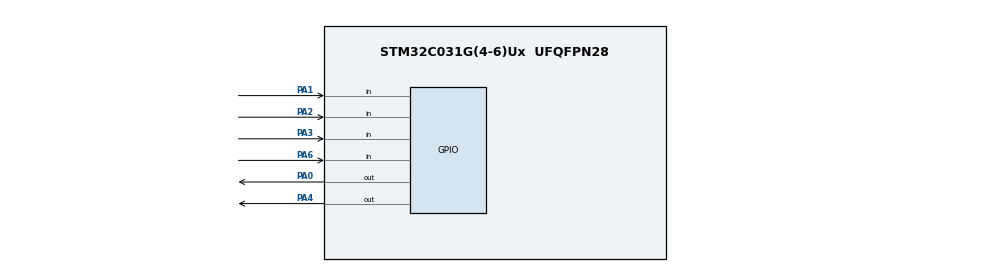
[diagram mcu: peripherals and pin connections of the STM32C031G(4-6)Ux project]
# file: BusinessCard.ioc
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Mcu.Family=STM32C0
Mcu.Name=STM32C031G(4-6)Ux
Mcu.Package=UFQFPN28
PA0.Signal=GPIO_Output
PA1.Signal=GPIO_Input
PA13.Mode=Serial_Wire
PA13.Signal=DEBUG_SWDIO
PA14-BOOT0.Mode=Serial_Wire
PA14-BOOT0.Signal=DEBUG_SWCLK
PA2.Signal=GPIO_Input
PA3.Signal=GPIO_Input
PA4.Signal=GPIO_Output
PA6.Signal=GPIO_Input
ProjectManager.HeapSize=0x200
ProjectManager.StackSize=0x400
ProjectManager.TargetToolchain=STM32CubeIDE
RCC.ADCFreq_Value=12000000
RCC.AHBFreq_Value=12000000
RCC.CortexFreq_Value=12000000
RCC.EXTERNAL_CLOCK_VALUE=12288000
RCC.HCLKFreq_Value=12000000
RCC.HSE_VALUE=8000000
RCC.HSI_VALUE=48000000
RCC.LSE_VALUE=32768
RCC.SYSCLKFreq_VALUE=12000000
board=custom

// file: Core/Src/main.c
/* USER CODE BEGIN Header */
/**
  ******************************************************************************
  * @file           : main.c
  * @brief          : Main program body
  ******************************************************************************
  * @attention
  *
  * Copyright (c) 2026 STMicroelectronics.
  * All rights reserved.
  *
  * This software is licensed under terms that can be found in the LICENSE file
  * in the root directory of this software component.
  * If no LICENSE file comes with this software, it is provided AS-IS.
  *
  ******************************************************************************
  */
/* USER CODE END Header */
#include "main.h"
#include <stdbool.h>
/* USER CODE BEGIN Includes */
#define DELAY_TIME 3
#define LOOP_NUM 30
/* USER CODE END Includes */

void SystemClock_Config(void);
static void MX_GPIO_Init(void);
void highZAll(void);
void pinInput(uint16_t GPIO_Pin);
void pinOutput(uint16_t GPIO_Pin);
void pinGrid(uint8_t grid[5][4], int loop);
void EnterSleepMode(void);

int main(void)
{

  /* MCU Configuration--------------------------------------------------------*/

  /* Reset of all peripherals, Initializes the Flash interface and the Systick. */
  HAL_Init();

  /* Configure the system clock */
  SystemClock_Config();

  /* Initialize all configured peripherals */
  MX_GPIO_Init();
  //ConfigureWakeupButton();

  /* Infinite loop */
  /* USER CODE BEGIN WHILE */
  //int i = 1;
  highZAll();
  uint8_t h[5][4] = {{1,0,0,1},
		  	  	  	 {1,0,0,1},
					 {1,1,1,1},
					 {1,0,0,1},
					 {1,0,0,1}};

  uint8_t i[5][4] = {{1,1,1,1},
		  	  	  	 {0,1,1,0},
					 {0,1,1,0},
					 {0,1,1,0},
					 {1,1,1,1}};

  uint8_t e[5][4] = {{0,1,1,0},
		  	  	     {0,1,1,0},
					 {0,1,1,0},
					 {0,0,0,0},
					 {0,1,1,0}};

  for (int x = 0; x < 6; x++) {
  		pinGrid(h,LOOP_NUM);
  		pinGrid(i,LOOP_NUM);
  		pinGrid(e,LOOP_NUM);
  	}
  EnterSleepMode();
  //HAL_PWR_EnterSTANDBYMode();
  //bool pressed = false;
  while (1)
  {

  }

//    /* USER CODE END WHILE */
//
//    /* USER CODE BEGIN 3 */

  /* USER CODE END 3 */
}

void EnterSleepMode(void)
{
  /* Suspend Tick increment to prevent wakeup by Systick interrupt */
  HAL_SuspendTick();

  /* Enter Sleep Mode, wake up on next interrupt */
  HAL_PWR_EnterSTOPMode(PWR_MAINREGULATOR_ON, PWR_SLEEPENTRY_WFI);

  /* Resume Tick interrupt */
  HAL_ResumeTick();
}

void pinGrid(uint8_t grid[5][4], int loops) {
	while (loops > 0) {
		for (int i = 1; i <=5; i++) {
			switch (i) {
				case 1:
					//[2,3,4,5]
					pinOutput(GPIO_PIN_1);
					HAL_GPIO_WritePin(GPIOA, GPIO_PIN_1, GPIO_PIN_SET);
					if (grid[0][0] == 1) {
						pinOutput(GPIO_PIN_2);
					}
					if (grid[0][1] == 1) {
						pinOutput(GPIO_PIN_3);
					}
					if (grid[0][2] == 1) {
						pinOutput(GPIO_PIN_4);
					}
					if (grid[0][3] == 1) {
						pinOutput(GPIO_PIN_5);
					}
					HAL_Delay(DELAY_TIME);
					highZAll();
					break;
				case 2:
					//[1,3,4,5]
					pinOutput(GPIO_PIN_2);
					HAL_GPIO_WritePin(GPIOA, GPIO_PIN_2, GPIO_PIN_SET);
					if (grid[1][0] == 1) {
						pinOutput(GPIO_PIN_1);
					}
					if (grid[1][1] == 1) {
						pinOutput(GPIO_PIN_3);
					}
					if (grid[1][2] == 1) {
						pinOutput(GPIO_PIN_4);
					}
					if (grid[1][3] == 1) {
						pinOutput(GPIO_PIN_5);
					}
					HAL_Delay(DELAY_TIME);
					highZAll();
					break;
				case 3:
					//[1,2,4,5]
					pinOutput(GPIO_PIN_3);
					HAL_GPIO_WritePin(GPIOA, GPIO_PIN_3, GPIO_PIN_SET);
					if (grid[2][0] == 1) {
						pinOutput(GPIO_PIN_1);
					}
					if (grid[2][1] == 1) {
						pinOutput(GPIO_PIN_2);
					}
					if (grid[2][2] == 1) {
						pinOutput(GPIO_PIN_4);
					}
					if (grid[2][3] == 1) {
						pinOutput(GPIO_PIN_5);
					}
					HAL_Delay(DELAY_TIME);
					highZAll();
					break;
				case 4:
					//[1,2,3,5]
					pinOutput(GPIO_PIN_4);
					HAL_GPIO_WritePin(GPIOA, GPIO_PIN_4, GPIO_PIN_SET);
					if (grid[3][0] == 1) {
						pinOutput(GPIO_PIN_1);
					}
					if (grid[3][1] == 1) {
						pinOutput(GPIO_PIN_2);
					}
					if (grid[3][2] == 1) {
						pinOutput(GPIO_PIN_3);
					}
					if (grid[3][3] == 1) {
						pinOutput(GPIO_PIN_5);
					}
					HAL_Delay(DELAY_TIME);
					highZAll();
					break;
				case 5:
					//[1,2,3,4]
					pinOutput(GPIO_PIN_5);
					HAL_GPIO_WritePin(GPIOA, GPIO_PIN_5, GPIO_PIN_SET);
					if (grid[4][0] == 1) {
						pinOutput(GPIO_PIN_1);
					}
					if (grid[4][1] == 1) {
						pinOutput(GPIO_PIN_2);
					}
					if (grid[4][2] == 1) {
						pinOutput(GPIO_PIN_3);
					}
					if (grid[4][3] == 1) {
						pinOutput(GPIO_PIN_4);
					}
					HAL_Delay(DELAY_TIME);
					highZAll();
					break;
				default:
					highZAll();
					HAL_Delay(DELAY_TIME);
			}
		}
	loops--;
	}
}

void pinOutput(uint16_t GPIO_Pin) {
    GPIO_InitTypeDef GPIO_InitStruct = {0};

    // Configure the pin as Output Push-Pull
    GPIO_InitStruct.Pin = GPIO_Pin;
    GPIO_InitStruct.Mode = GPIO_MODE_OUTPUT_PP;
    GPIO_InitStruct.Pull = GPIO_NOPULL; // Or GPIO_PULLUP/PULLDOWN as needed
    GPIO_InitStruct.Speed = GPIO_SPEED_FREQ_LOW; // Adjust speed as necessary

    HAL_GPIO_Init(GPIOA, &GPIO_InitStruct);

    // Optional: Set an initial state (e.g., LOW)
    HAL_GPIO_WritePin(GPIOA, GPIO_Pin, GPIO_PIN_RESET);
}

void pinInput(uint16_t GPIO_Pin) {
    GPIO_InitTypeDef GPIO_InitStruct = {0};

    // Configure the pin as Input
    GPIO_InitStruct.Pin = GPIO_Pin;
    GPIO_InitStruct.Mode = GPIO_MODE_INPUT;
    GPIO_InitStruct.Pull = GPIO_NOPULL; // Or GPIO_PULLUP/PULLDOWN as needed

    HAL_GPIO_Init(GPIOA, &GPIO_InitStruct);
}

void highZAll(void) {
	pinInput(GPIO_PIN_1);
	pinInput(GPIO_PIN_2);
	pinInput(GPIO_PIN_3);
	pinInput(GPIO_PIN_4);
	pinInput(GPIO_PIN_5);
}

void SystemClock_Config(void)
{
  RCC_OscInitTypeDef RCC_OscInitStruct = {0};
  RCC_ClkInitTypeDef RCC_ClkInitStruct = {0};

  __HAL_FLASH_SET_LATENCY(FLASH_LATENCY_0);

  /** Initializes the RCC Oscillators according to the specified parameters
  * in the RCC_OscInitTypeDef structure.
  */
  RCC_OscInitStruct.OscillatorType = RCC_OSCILLATORTYPE_HSI;
  RCC_OscInitStruct.HSIState = RCC_HSI_ON;
  RCC_OscInitStruct.HSIDiv = RCC_HSI_DIV4;
  RCC_OscInitStruct.HSICalibrationValue = RCC_HSICALIBRATION_DEFAULT;
  if (HAL_RCC_OscConfig(&RCC_OscInitStruct) != HAL_OK)
  {
    Error_Handler();
  }

  /** Initializes the CPU, AHB and APB buses clocks
  */
  RCC_ClkInitStruct.ClockType = RCC_CLOCKTYPE_HCLK|RCC_CLOCKTYPE_SYSCLK
                              |RCC_CLOCKTYPE_PCLK1;
  RCC_ClkInitStruct.SYSCLKSource = RCC_SYSCLKSOURCE_HSI;
  RCC_ClkInitStruct.SYSCLKDivider = RCC_SYSCLK_DIV1;
  RCC_ClkInitStruct.AHBCLKDivider = RCC_HCLK_DIV1;
  RCC_ClkInitStruct.APB1CLKDivider = RCC_APB1_DIV1;

  if (HAL_RCC_ClockConfig(&RCC_ClkInitStruct, FLASH_LATENCY_0) != HAL_OK)
  {
    Error_Handler();
  }
}

static void MX_GPIO_Init(void)
{
  GPIO_InitTypeDef GPIO_InitStruct = {0};

  /* GPIO Ports Clock Enable */
  __HAL_RCC_GPIOA_CLK_ENABLE();

  /*Configure GPIO pin Output Level */
  HAL_GPIO_WritePin(GPIOA, GPIO_PIN_5|GPIO_PIN_4| GPIO_PIN_1|GPIO_PIN_2|GPIO_PIN_3, GPIO_PIN_RESET);

  /*Configure GPIO pins : PA0 PA4 */
  GPIO_InitStruct.Pin = GPIO_PIN_5|GPIO_PIN_4| GPIO_PIN_1|GPIO_PIN_2|GPIO_PIN_3;
  GPIO_InitStruct.Mode = GPIO_MODE_OUTPUT_PP;
  GPIO_InitStruct.Pull = GPIO_NOPULL;
  GPIO_InitStruct.Speed = GPIO_SPEED_FREQ_LOW;
  HAL_GPIO_Init(GPIOA, &GPIO_InitStruct);

  /*Configure GPIO pins : PA1 PA2 PA3 PA6 */
//  HAL_PWR_EnableWakeUpPin();
  GPIO_InitStruct.Pin = GPIO_PIN_2;
  GPIO_InitStruct.Mode = GPIO_MODE_INPUT;
  GPIO_InitStruct.Pull = GPIO_NOPULL;
  HAL_GPIO_Init(GPIOF, &GPIO_InitStruct);

}

void Error_Handler(void)
{
  __disable_irq();
  while (1)
  {
  }
}
